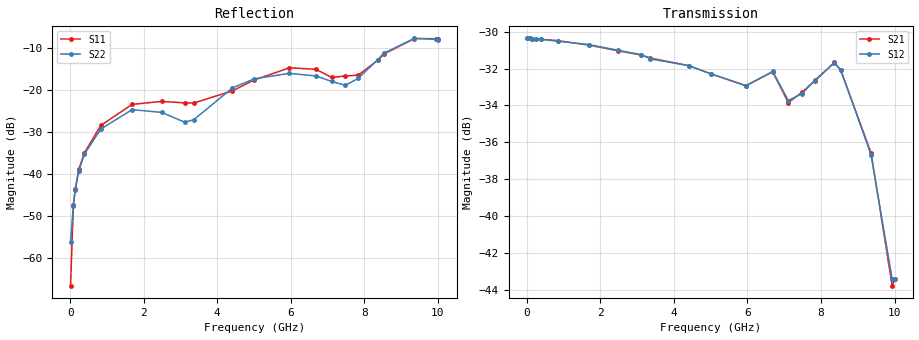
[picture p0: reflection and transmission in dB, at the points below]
! Device ID: PE43704
! Dir: z:\PE43704\PE43704_Char_1_20130516\PE43704\AMB\3p400V\29p50dB
! Serial: 14
! Insertion: A
! Impedance: 50 ohm
! Temp: Amb
! VDD: 3.400V
! Attenuation Step: 29.50dB
! IDD: 1.140121e-01mA
#  Hz  S  RI  R  50
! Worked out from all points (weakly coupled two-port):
!   401 points, 10 MHz to 10.01 GHz, reference 50 ohm
!   highest |S21| = -30.36 dB at 10 MHz (marker M1); lowest = -43.7 dB at 9.935 GHz (marker M2)
!   lowest |S11| = -66.5 dB at 10 MHz (marker M3), VSWR 1.00, Z = 50 + j0.046 ohm
!   |S11| at or under -10 dB: start of sweep to 8.738 GHz
!   |S22| runs from -56.0 to -7.6 dB; largest |S21 - S12| = 0.00085
!   S11 on the Smith chart (normalised r, x): 10 MHz: 1.00, +0.00; 7.485 GHz: 0.78, +0.15; 8.535 GHz: 0.79, +0.45; 9.36 GHz: 0.54, +0.48; 10.01 GHz: 0.46, +0.27
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1e7  -0.000115 0.00046  0.0303 -9.33e-05  0.0303 -7.37e-05  -0.00152 0.000451
8.5e7  -5.11e-05 0.00433  0.0303 -0.000659  0.0303 -0.00064  -0.00134 0.00399
1.35e8  -0.000258 0.00662  0.0302 -0.00101  0.0302 -0.00101  -0.00158 0.00627
2.35e8  -0.00192 0.0113  0.0301 -0.00176  0.0301 -0.00171  -0.00303 0.0107
3.85e8  -0.00503 0.0173  0.03 -0.00284  0.03 -0.00281  -0.00608 0.0163
8.35e8  -0.0252 0.0289  0.0293 -0.00585  0.0292 -0.00583  -0.0237 0.0254
1.685e9  -0.0664 0.0151  0.0269 -0.011  0.027 -0.011  -0.0584 0.00817
2.485e9  -0.0735 -0.00654  0.0237 -0.015  0.0238 -0.015  -0.0542 -0.00714
3.11e9  -0.0707 -0.00656  0.0208 -0.0177  0.0209 -0.0177  -0.0417 0.00341
3.36e9  -0.0707 -0.000762  0.0195 -0.0184  0.0194 -0.0183  -0.043 0.0121
4.41e9  -0.0883 0.0436  0.015 -0.0207  0.015 -0.0207  -0.0901 0.0572
5.01e9  -0.1118 0.072  0.0127 -0.0207  0.0127 -0.0207  -0.1228 0.0612
5.96e9  -0.1592 0.0948  0.00825 -0.021  0.00855 -0.0209  -0.1486 0.0571
6.685e9  -0.159 0.08  0.007 -0.0236  0.00682 -0.0237  -0.138 0.0545
7.11e9  -0.1285 0.0611  0.00196 -0.0202  0.0018 -0.0205  -0.1066 0.0699
7.485e9  -0.1152 0.0932  0.00288 -0.0215  0.00279 -0.0213  -0.0764 0.0858
7.835e9  -0.0723 0.1334  0.0028 -0.0231  0.00295 -0.0232  -0.0614 0.1244
8.36e9  -0.0405 0.2233  -0.00506 -0.0256  -0.005 -0.0255  -0.0776 0.2185
8.535e9  -0.0492 0.2652  -0.00831 -0.0234  -0.00803 -0.0236  -0.096 0.2599
9.36e9  -0.1878 0.3677  -0.0108 -0.0102  -0.0108 -0.00994  -0.2421 0.3374
9.935e9  -0.3124 0.2678  -0.00236 -0.00605  -0.00282 -0.00614  -0.3497 0.2034
1.001e10  -0.3249 0.2412  -0.00166 -0.00657  -0.00146 -0.00661  -0.3582 0.1752
